One B-rep face of a CAD part: STEP entity #267.
In plain terms, the planar face has unit normal (1, 0, 0).
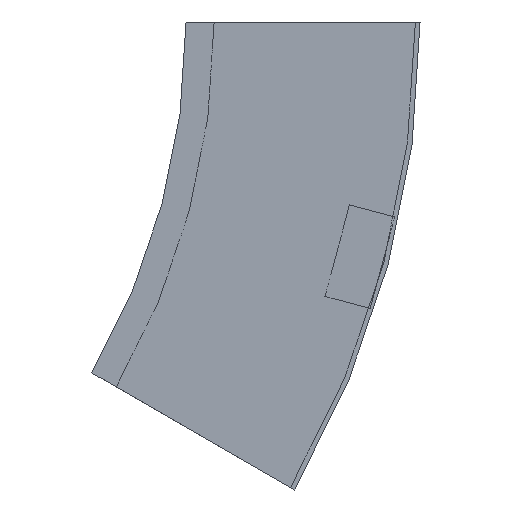
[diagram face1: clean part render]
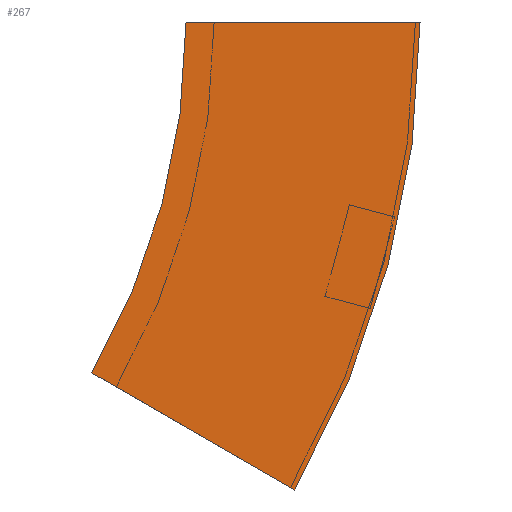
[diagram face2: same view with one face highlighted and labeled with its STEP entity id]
Its self-contained STEP definition (entity closure, numbers rounded to 3 decimals):
#49 = VERTEX_POINT ( 'NONE', #534 ) ;
#80 = CIRCLE ( 'NONE', #309, 300. ) ;
#104 = EDGE_CURVE ( 'NONE', #302, #49, #196, .T. ) ;
#110 = CARTESIAN_POINT ( 'NONE',  ( 0., 300., 0. ) ) ;
#132 = EDGE_CURVE ( 'NONE', #49, #192, #80, .T. ) ;
#138 = DIRECTION ( 'NONE',  ( 0., 0., 1. ) ) ;
#156 = CIRCLE ( 'NONE', #529, 400. ) ;
#165 = CARTESIAN_POINT ( 'NONE',  ( 0., -100., 0. ) ) ;
#192 = VERTEX_POINT ( 'NONE', #549 ) ;
#196 = LINE ( 'NONE', #165, #482 ) ;
#198 = DIRECTION ( 'NONE',  ( 1., 0., 0. ) ) ;
#207 = DIRECTION ( 'NONE',  ( 0., -1., 0. ) ) ;
#211 = CARTESIAN_POINT ( 'NONE',  ( 0., -46.41, -200. ) ) ;
#219 = VECTOR ( 'NONE', #369, 1000. ) ;
#227 = ORIENTED_EDGE ( 'NONE', *, *, #544, .T. ) ;
#249 = DIRECTION ( 'NONE',  ( 1., 0., 0. ) ) ;
#250 = LINE ( 'NONE', #211, #219 ) ;
#255 = DIRECTION ( 'NONE',  ( 0., 1., 0. ) ) ;
#267 = ADVANCED_FACE ( 'NONE', ( #508 ), #384, .F. ) ;
#299 = ORIENTED_EDGE ( 'NONE', *, *, #132, .F. ) ;
#302 = VERTEX_POINT ( 'NONE', #389 ) ;
#309 = AXIS2_PLACEMENT_3D ( 'NONE', #110, #249, #207 ) ;
#321 = CARTESIAN_POINT ( 'NONE',  ( 0., 300., 0. ) ) ;
#342 = DIRECTION ( 'NONE',  ( -1., 0., 0. ) ) ;
#352 = ORIENTED_EDGE ( 'NONE', *, *, #449, .T. ) ;
#369 = DIRECTION ( 'NONE',  ( 0., 0.866, 0.5 ) ) ;
#370 = DIRECTION ( 'NONE',  ( 0., -1., 0. ) ) ;
#372 = CARTESIAN_POINT ( 'NONE',  ( 0., -46.41, -200. ) ) ;
#384 = PLANE ( 'NONE',  #541 ) ;
#389 = CARTESIAN_POINT ( 'NONE',  ( 0., -100., 0. ) ) ;
#399 = ORIENTED_EDGE ( 'NONE', *, *, #104, .F. ) ;
#417 = CARTESIAN_POINT ( 'NONE',  ( 0., -100., 0. ) ) ;
#436 = VERTEX_POINT ( 'NONE', #372 ) ;
#449 = EDGE_CURVE ( 'NONE', #302, #436, #156, .T. ) ;
#467 = EDGE_LOOP ( 'NONE', ( #299, #399, #352, #227 ) ) ;
#482 = VECTOR ( 'NONE', #255, 1000. ) ;
#508 = FACE_OUTER_BOUND ( 'NONE', #467, .T. ) ;
#529 = AXIS2_PLACEMENT_3D ( 'NONE', #321, #198, #370 ) ;
#534 = CARTESIAN_POINT ( 'NONE',  ( 0., 0., 0. ) ) ;
#541 = AXIS2_PLACEMENT_3D ( 'NONE', #417, #342, #138 ) ;
#544 = EDGE_CURVE ( 'NONE', #436, #192, #250, .T. ) ;
#549 = CARTESIAN_POINT ( 'NONE',  ( 0., 40.192, -150. ) ) ;
